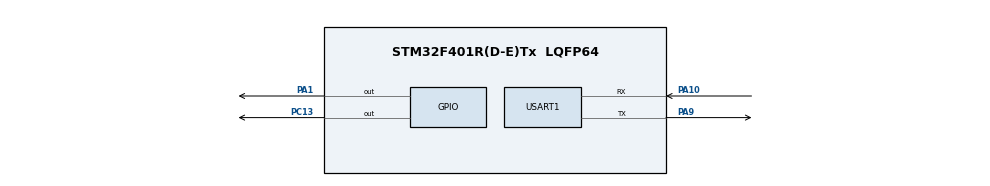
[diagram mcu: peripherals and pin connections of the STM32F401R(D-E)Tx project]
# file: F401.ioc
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Mcu.Family=STM32F4
Mcu.Name=STM32F401R(D-E)Tx
Mcu.Package=LQFP64
NVIC.PriorityGroup=NVIC_PRIORITYGROUP_0
NVIC.USART1_IRQn=true\:0\:0\:false\:false\:true\:true\:true\:true
PA1.GPIO_Speed=GPIO_SPEED_FREQ_LOW
PA1.Signal=GPIO_Output
PA10.Mode=Asynchronous
PA10.Signal=USART1_RX
PA13.GPIO_Label=TMS
PA13.Mode=Serial_Wire
PA13.Signal=SYS_JTMS-SWDIO
PA14.GPIO_Label=TCK
PA14.Mode=Serial_Wire
PA14.Signal=SYS_JTCK-SWCLK
PA9.Mode=Asynchronous
PA9.Signal=USART1_TX
PB3.GPIO_Label=SWO
PB3.Signal=SYS_JTDO-SWO
PC13-ANTI_TAMP.Signal=GPIO_Output
PC14-OSC32_IN.Signal=RCC_OSC32_IN
PC15-OSC32_OUT.Signal=RCC_OSC32_OUT
PH0\ -\ OSC_IN.Mode=HSE-External-Oscillator
PH0\ -\ OSC_IN.Signal=RCC_OSC_IN
PH1\ -\ OSC_OUT.Mode=HSE-External-Oscillator
PH1\ -\ OSC_OUT.Signal=RCC_OSC_OUT
ProjectManager.HeapSize=0x200
ProjectManager.StackSize=0x400
ProjectManager.TargetToolchain=Makefile
RCC.48MHZClocksFreq_Value=24000000
RCC.AHBFreq_Value=84000000
RCC.APB1CLKDivider=RCC_HCLK_DIV2
RCC.APB1Freq_Value=42000000
RCC.APB1TimFreq_Value=84000000
RCC.APB2Freq_Value=84000000
RCC.APB2TimFreq_Value=84000000
RCC.CortexFreq_Value=84000000
RCC.HCLKFreq_Value=84000000
RCC.HSE_VALUE=8000000
RCC.HSI_VALUE=16000000
RCC.LSE_VALUE=32768
RCC.PLLM=8
RCC.PLLN=168
RCC.PLLQ=7
RCC.PLLSourceVirtual=RCC_PLLSOURCE_HSE
RCC.SYSCLKFreq_VALUE=84000000
RCC.SYSCLKSource=RCC_SYSCLKSOURCE_PLLCLK
RCC.VCOOutputFreq_Value=168000000
USART1.VirtualMode=VM_ASYNC
board=NUCLEO-F401RE

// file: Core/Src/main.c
/* USER CODE BEGIN Header */
/**
 * *****************************************************************************
 * @file           : main.c
 * @brief          : Main program body
 ******************************************************************************
 * @attention
 *
 * Copyright (c) 2026 STMicroelectronics.
 * All rights reserved.
 *
 * This software is licensed under terms that can be found in the LICENSE file
 * in the root directory of this software component.
 * If no LICENSE file comes with this software, it is provided AS-IS.
 *
 ******************************************************************************
 */
/* USER CODE END Header */
#include "main.h"
#include "usart.h"
#include "gpio.h"
#include "dht11.h"
#include "uart_handler.h"
#include <stdio.h>
#include <string.h>

DHT11_Data_t dht_data;

/* USER CODE BEGIN PV */
// Variables for pure interrupt-driven UART handler
extern SensorData_t g_sensor_data;

char debug_buffer[64];
/* USER CODE END PV */

void SystemClock_Config(void);
/* USER CODE BEGIN PFP */
void Debug_Send(const char *message);
/* USER CODE END PFP */

/* USER CODE BEGIN 0 */
// Hàm hỗ trợ printf qua UART
int _write(int file, char *ptr, int len)
{
  HAL_UART_Transmit(&huart1, (uint8_t *)ptr, len, HAL_MAX_DELAY);
  return len;
}

// UART RX Callback is now in uart_handler.c for pure interrupt-driven operation

// Debug function for sending text via UART
void Debug_Send(const char *message) {
  HAL_UART_Transmit(&huart1, (uint8_t*)message, strlen(message), 100);
}
/* USER CODE END 0 */

int main(void)
{

  /* MCU Configuration--------------------------------------------------------*/

  /* Reset of all peripherals, Initializes the Flash interface and the Systick. */
  HAL_Init();

  /* Configure the system clock */
  SystemClock_Config();

  /* Initialize all configured peripherals */
  MX_GPIO_Init();
  MX_USART1_UART_Init();
  /* USER CODE BEGIN 2 */
  // Initialize DHT11
  DHT11_Init();

  // Initialize LED (PA5)
  HAL_GPIO_WritePin(GPIOA, GPIO_PIN_5, GPIO_PIN_RESET);
  g_sensor_data.led_state = 0;

  // Initialize sensor data with defaults
  g_sensor_data.temperature = 25;
  g_sensor_data.humidity = 50;
  g_sensor_data.led_state = 0;

  dht_data.temperature = 0;
  dht_data.humidity = 0;
  dht_data.valid = false;

  // Initialize UART Handler (MUST BE LAST - starts interrupt reception)
  UART_Handler_Init(&huart1);

  // Send startup message via UART
  // printf("\r\n\r\n========================================\r\n");
  // printf("STM32F401RE - Pure Interrupt-Driven Mode\r\n");
  // printf("USART1: PA9(TX), PA10(RX) @ 115200\r\n");
  // printf("DHT11: PA1, LED: PA5\r\n");
  // printf("NEW Protocol: Request[AA 01 00 55]\r\n");
  // printf("              Response[AA 01 03 TEMP HUM LED 55]\r\n");
  // printf("              LED Control[AA 02 01 STATE 55]\r\n");
  // printf("Ready for pure interrupt-driven operation...\r\n");
  // printf("========================================\r\n");
  /* USER CODE END 2 */

  /* Infinite loop */
  /* USER CODE BEGIN WHILE */
  while (1)
  {
    // Process UART RX buffer
    UART_Process();
    UART_Process_Frame();

    // Optional: Small delay to prevent excessive power consumption
    HAL_Delay(10);

    /* USER CODE END WHILE */

  }
}

void SystemClock_Config(void)
{
  RCC_OscInitTypeDef RCC_OscInitStruct = {0};
  RCC_ClkInitTypeDef RCC_ClkInitStruct = {0};

  /** Configure the main internal regulator output voltage
   */
  __HAL_RCC_PWR_CLK_ENABLE();
  __HAL_PWR_VOLTAGESCALING_CONFIG(PWR_REGULATOR_VOLTAGE_SCALE2);

  /** Initializes the RCC Oscillators according to the specified parameters
   * in the RCC_OscInitTypeDef structure.
   */
  RCC_OscInitStruct.OscillatorType = RCC_OSCILLATORTYPE_HSE;
  RCC_OscInitStruct.HSEState = RCC_HSE_ON;
  RCC_OscInitStruct.PLL.PLLState = RCC_PLL_ON;
  RCC_OscInitStruct.PLL.PLLSource = RCC_PLLSOURCE_HSE;
  RCC_OscInitStruct.PLL.PLLM = 8;
  RCC_OscInitStruct.PLL.PLLN = 168;
  RCC_OscInitStruct.PLL.PLLP = RCC_PLLP_DIV4;
  RCC_OscInitStruct.PLL.PLLQ = 7;
  if (HAL_RCC_OscConfig(&RCC_OscInitStruct) != HAL_OK)
  {
    Error_Handler();
  }

  /** Initializes the CPU, AHB and APB buses clocks
   */
  RCC_ClkInitStruct.ClockType = RCC_CLOCKTYPE_HCLK|RCC_CLOCKTYPE_SYSCLK
  |RCC_CLOCKTYPE_PCLK1|RCC_CLOCKTYPE_PCLK2;
  RCC_ClkInitStruct.SYSCLKSource = RCC_SYSCLKSOURCE_PLLCLK;
  RCC_ClkInitStruct.AHBCLKDivider = RCC_SYSCLK_DIV1;
  RCC_ClkInitStruct.APB1CLKDivider = RCC_HCLK_DIV2;
  RCC_ClkInitStruct.APB2CLKDivider = RCC_HCLK_DIV1;

  if (HAL_RCC_ClockConfig(&RCC_ClkInitStruct, FLASH_LATENCY_2) != HAL_OK)
  {
    Error_Handler();
  }
}

/* USER CODE BEGIN 4 */
// Pure interrupt-driven approach - no manual UART restart needed
// All UART handling is done automatically by ISR
/* USER CODE END 4 */

void Error_Handler(void)
{
  /* USER CODE BEGIN Error_Handler_Debug */
  __disable_irq();
  while (1) {
    // Blink LED rapidly on error - PA5
    HAL_GPIO_TogglePin(GPIOA, GPIO_PIN_5);
    HAL_Delay(100);
  }
  /* USER CODE END Error_Handler_Debug */
}
